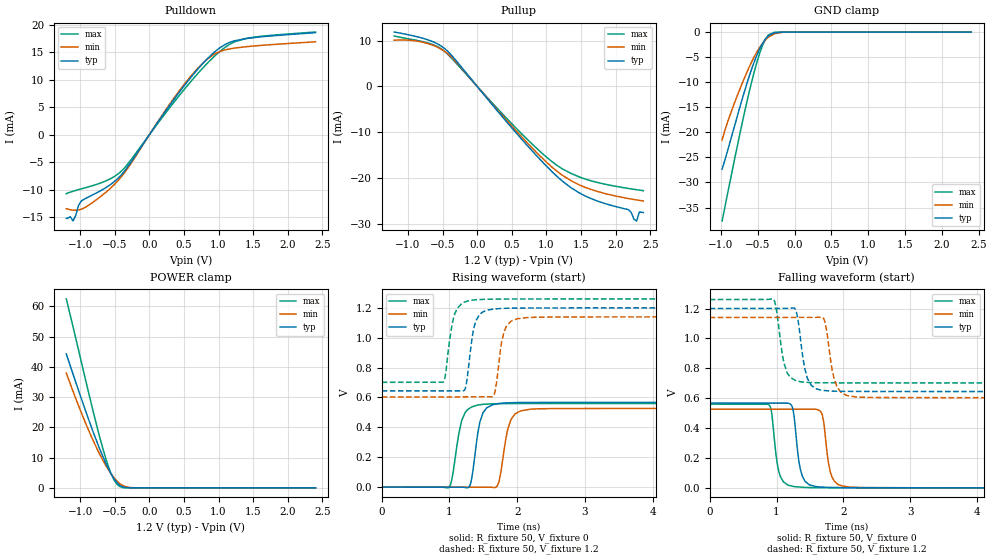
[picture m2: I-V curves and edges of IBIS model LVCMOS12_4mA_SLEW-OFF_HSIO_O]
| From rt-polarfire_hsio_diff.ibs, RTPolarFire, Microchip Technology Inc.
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|   Model LVCMOS12_4mA_SLEW-OFF_HSIO_O
[Model]   LVCMOS12_4mA_SLEW-OFF_HSIO_O
Model_type   Output
Polarity   Non-Inverting
Enable   Active-High
Vmeas =   0.6
Cref =   5p
Rref =   1M
|   typ   min   max
C_comp_pullup   1.335e-12   1.335e-12   1.380e-12
C_comp_pulldown  1.335e-12   1.335e-12   1.380e-12
[Temperature Range]  25C   125C   -55C
[Voltage Range]  1.2   1.14   1.26
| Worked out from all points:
|   slope of the pulldown table from 0 to 0.18 V, typ, clamps not added: 54.1 ohm
|   slope of the pullup table from 0 to 0.18 V, typ, clamps not added: 54.3 ohm
|   GND clamp passes 1 mA (typ) near -0.37 V on its own axis
|   POWER clamp passes 1 mA (typ) near -0.44 V on its own axis
|   rising waveform, R_fixture 50, V_fixture 0: 20-80 % time 115ps typ, 125ps min, 125ps max; typ from 0 V to 0.567 V
|   rising waveform, R_fixture 50, V_fixture 1.2: 20-80 % time 106ps typ, 103ps min, 113ps max; typ from 0.644 V to 1.2 V
|   falling waveform, R_fixture 50, V_fixture 0: 20-80 % time 94.1ps typ, 94.2ps min, 91.7ps max; typ from 0.567 V to 0 V
|   falling waveform, R_fixture 50, V_fixture 1.2: 20-80 % time 116ps typ, 122ps min, 115ps max; typ from 1.2 V to 0.644 V
[GND Clamp]
| Voltage   I(typ)   I(min)   I(max)
-984.4mV  -27.36mA   -21.51mA   -37.68mA
-905.6mV  -23.44mA   -17.74mA   -31.9mA
-826.9mV  -19.32mA   -14.54mA   -26.19mA
-708.7mV  -13.22mA   -10.13mA   -17.93mA
-590.6mV  -7.694mA   -6.183mA   -10.37mA
-511.9mV  -4.598mA   -3.964mA   -6.023mA
-472.5mV  -3.303mA   -3.022mA   -4.164mA
-393.7mV  -1.354mA   -1.536mA   -1.373mA
-354.4mV  -738.1uA   -1.006mA   -579.2uA
-275.6mV  -148.2uA   -350.2uA   -51.36uA
-157.5mV  -6.952uA   -42.62uA   -774.1nA
2.4V      0A         0A         0A
[POWER Clamp]
| Voltage   I(typ)   I(min)   I(max)
-1.2V     44.33mA    38.01mA    62.52mA
-1.063V   34.96mA    29.56mA    49.5mA
-905.6mV  24.47mA    20.57mA    34.21mA
-787.5mV  17.03mA    14.47mA    23.07mA
-669.4mV  10.26mA    9.06mA     12.82mA
-590.6mV  6.299mA    5.966mA    6.995mA
-551.3mV  4.569mA    4.604mA    4.604mA
-472.5mV  1.839mA    2.331mA    1.325mA
-433.1mV  941.2uA    1.473mA    512.6uA
-354.4mV  127.4uA    466.4uA    28.07uA
-196.9mV  963.6nA    26.23uA    495.2nA
2.4V      0A         0A         0A
[Pullup]
| Voltage   I(typ)   I(min)   I(max)
-1.2V     11.9mA     10.11mA    11.03mA
-787.5mV  10.54mA    9.662mA    9.792mA
-590.6mV  9.428mA    8.683mA    8.826mA
-433.1mV  7.788mA    7.254mA    7.146mA
675mV     -12.08mA   -11.54mA   -10.83mA
1.012V    -17.58mA   -16.69mA   -15.58mA
1.239V    -20.78mA   -19.48mA   -18.08mA
1.633V    -24.41mA   -22.43mA   -20.55mA
2.184V    -26.9mA    -24.47mA   -22.27mA
2.303V    -29.38mA   -24.78mA   -22.54mA
2.342V    -27.42mA   -24.87mA   -22.63mA
2.4V      -27.54mA   -25.01mA   -22.75mA
[Pulldown]
| Voltage   I(typ)   I(min)   I(max)
-1.2V     -15.23mA   -13.47mA   -10.74mA
-1.142V   -14.92mA   -13.66mA   -10.45mA
-1.103V   -15.71mA   -13.74mA   -10.29mA
-1.024V   -12.89mA   -13.7mA    -9.995mA
-905.6mV  -11.5mA    -13.07mA   -9.582mA
-590.6mV  -9.322mA   -10.07mA   -8.184mA
-393.7mV  -7.136mA   -7.475mA   -6.504mA
525mV     9.268mA    9.529mA    8.58mA
787.5mV   13.18mA    13.21mA    12.37mA
1.012V    15.78mA    15.13mA    15.11mA
1.397V    17.52mA    16.04mA    17.54mA
2.4V      18.6mA     16.94mA    18.72mA
[Ramp]
dV/dt_r   0.340474/0.114795n  0.316046/0.124803n  0.336016/0.125226n
dV/dt_f   0.333655/0.115787n  0.321999/0.122288n  0.335224/0.114521n
R_load = 50
[Rising Waveform]
R_fixture = 50
V_fixture = 0
V_fixture_min = 0
V_fixture_max = 0
| Time   V(typ)   V(min)   V(max)
0s        1.164uV    2.596uV    1.666uV
986ps     -676.2uV   -507.3uV   -4.508mV
1.034ns   -709.2uV   -532.1uV   49.08mV
1.18ns    -809.5uV   -607.6uV   444.7mV
1.292ns   2.108mV    -665.5uV   526.3mV
1.49ns    491.4mV    -767.9uV   553.8mV
1.705ns   557.2mV    7.534mV    558.2mV
1.91ns    564.7mV    455.6mV    559.2mV
2.2ns     566.3mV    521.8mV    559.4mV
10ns      567.5mV    526.7mV    560mV
[Rising Waveform]
R_fixture = 50
V_fixture = 1.2
V_fixture_min = 1.14
V_fixture_max = 1.26
| Time   V(typ)   V(min)   V(max)
0s        643.9mV    603.3mV    701.3mV
909ps     644.2mV    603.8mV    704mV
1.058ns   644.3mV    603.9mV    1.129V
1.229ns   655.4mV    604mV      1.24V
1.324ns   965.5mV    604.1mV    1.251V
1.444ns   1.157V     604.1mV    1.255V
1.641ns   1.191V     606.6mV    1.258V
1.803ns   1.197V     1.037V     1.259V
2.107ns   1.199V     1.133V     1.259V
10ns      1.2V       1.14V      1.26V
[Falling Waveform]
R_fixture = 50
V_fixture = 0
V_fixture_min = 0
V_fixture_max = 0
| Time   V(typ)   V(min)   V(max)
0s        567.5mV    526.7mV    560mV
891ps     566.9mV    526.4mV    553.2mV
1.035ns   566.8mV    526.3mV    107.5mV
1.264ns   473.6mV    526.2mV    8.17mV
1.336ns   174.3mV    526.2mV    5.848mV
1.425ns   44.6mV     526.2mV    2.977mV
1.672ns   4.932mV    501.9mV    1.278mV
1.805ns   2.342mV    106mV      1.023mV
1.986ns   1.41mV     11.99mV    707.7uV
10ns      1.935uV    4.516uV    2.517uV
[Falling Waveform]
R_fixture = 50
V_fixture = 1.2
V_fixture_min = 1.14
V_fixture_max = 1.26
| Time   V(typ)   V(min)   V(max)
0s        1.2V       1.14V      1.26V
960ps     1.201V     1.141V     1.26V
1.159ns   1.201V     1.141V     769.3mV
1.293ns   1.184V     1.141V     716.1mV
1.39ns    886.7mV    1.141V     707.9mV
1.519ns   686.1mV    1.141V     704.4mV
1.701ns   652.1mV    1.135V     703.1mV
1.903ns   646.5mV    677.4mV    702.6mV
2.191ns   645.3mV    607.8mV    702.1mV
10ns      643.9mV    603.3mV    701.3mV
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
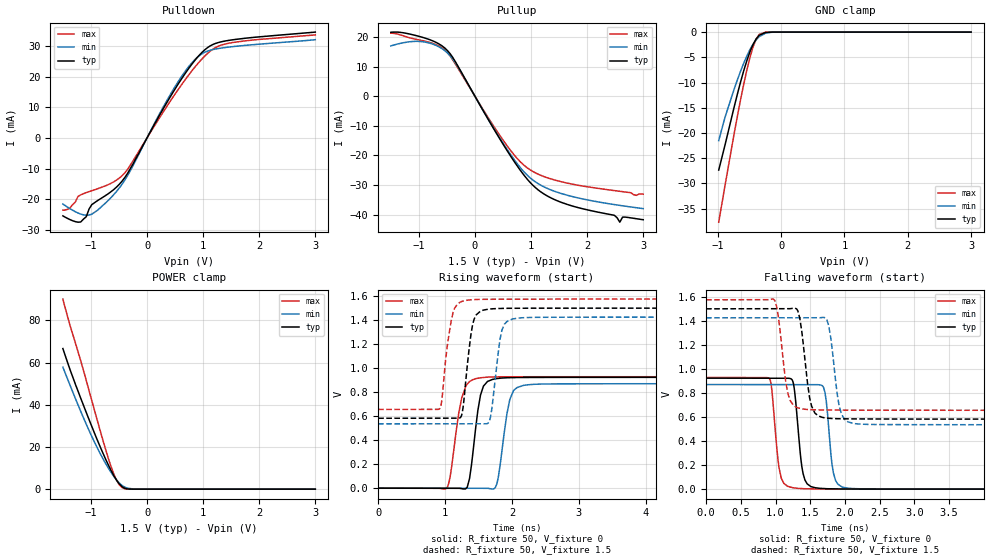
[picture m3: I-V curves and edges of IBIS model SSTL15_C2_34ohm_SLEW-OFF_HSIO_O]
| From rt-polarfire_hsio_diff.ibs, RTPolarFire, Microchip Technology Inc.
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|   Model SSTL15_C2_34ohm_SLEW-OFF_HSIO_O
[Model]   SSTL15_C2_34ohm_SLEW-OFF_HSIO_O
Model_type   Output
Polarity   Non-Inverting
Enable   Active-High
Vmeas =   0.75
Cref =   5p
Rref =   50
Vref =   0.75
|   typ   min   max
C_comp_pullup   1.335e-12   1.335e-12   1.380e-12
C_comp_pulldown  1.335e-12   1.335e-12   1.380e-12
[Temperature Range]  25C   125C   -55C
[Voltage Range]  1.5   1.425   1.575
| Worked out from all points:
|   slope of the pulldown table from 0 to 0.225 V, typ, clamps not added: 30.1 ohm
|   slope of the pullup table from 0 to 0.225 V, typ, clamps not added: 30.2 ohm
|   GND clamp passes 1 mA (typ) near -0.37 V on its own axis
|   POWER clamp passes 1 mA (typ) near -0.43 V on its own axis
|   rising waveform, R_fixture 50, V_fixture 0: 20-80 % time 126ps typ, 134ps min, 146ps max; typ from 0 V to 0.923 V
|   rising waveform, R_fixture 50, V_fixture 1.5: 20-80 % time 110ps typ, 114ps min, 120ps max; typ from 0.582 V to 1.5 V
|   falling waveform, R_fixture 50, V_fixture 0: 20-80 % time 91.1ps typ, 85.8ps min, 88.4ps max; typ from 0.923 V to 0 V
|   falling waveform, R_fixture 50, V_fixture 1.5: 20-80 % time 112ps typ, 111ps min, 114ps max; typ from 1.5 V to 0.582 V
[GND Clamp]
| Voltage   I(typ)   I(min)   I(max)
-984.4mV  -27.37mA   -21.52mA   -37.7mA
-885.9mV  -22.43mA   -16.92mA   -30.48mA
-738.3mV  -14.72mA   -11.21mA   -19.96mA
-639.8mV  -9.903mA   -7.76mA    -13.42mA
-590.6mV  -7.7mA     -6.188mA   -10.38mA
-492.2mV  -3.93mA    -3.481mA   -5.066mA
-443mV    -2.467mA   -2.402mA   -2.955mA
-393.7mV  -1.355mA   -1.538mA   -1.375mA
-344.5mV  -621.9uA   -897uA     -448.3uA
-246.1mV  -72.57uA   -218.4uA   -18.4uA
-49.22mV  -334.5nA   -3.793uA   -95.68nA
3V        0A         0A         0A
[POWER Clamp]
| Voltage   I(typ)   I(min)   I(max)
-1.5V     66.64mA    57.8mA     90.1mA
-1.378V   57.06mA    49.6mA     78.07mA
-1.28V    49.9mA     43.13mA    69.49mA
-1.034V   32.99mA    27.83mA    46.7mA
-836.7mV  20.16mA    16.97mA    27.85mA
-689.1mV  11.42mA    9.956mA    14.55mA
-590.6mV  6.331mA    6.012mA    7.055mA
-541.4mV  4.184mA    4.318mA    4.125mA
-443mV    1.134mA    1.688mA    703.5uA
-344.5mV  93.53uA    432.5uA    21.45uA
-49.22mV  620.3nA    2.506uA    250nA
3V        0A         0A         0A
[Pullup]
| Voltage   I(typ)   I(min)   I(max)
-1.5V     21.63mA    17.01mA    21.33mA
-935.2mV  19.92mA    18.44mA    18.8mA
-492.2mV  15.48mA    14.7mA     14.8mA
-344.5mV  11.55mA    11.2mA     10.76mA
609.4mV   -19.45mA   -18.96mA   -17.67mA
890.6mV   -27.08mA   -25.9mA    -23.58mA
1.172V    -32.3mA    -30.05mA   -26.72mA
1.648V    -36.59mA   -33.48mA   -29.37mA
2.484V    -40.25mA   -36.62mA   -31.9mA
2.583V    -42.58mA   -36.9mA    -32.14mA
2.632V    -40.87mA   -37.04mA   -32.26mA
3V        -41.75mA   -38mA      -33.11mA
[Pulldown]
| Voltage   I(typ)   I(min)   I(max)
-1.5V     -25.45mA   -21.56mA   -23.56mA
-1.378V   -26.63mA   -23.05mA   -22.94mA
-1.181V   -27.44mA   -24.88mA   -18.59mA
-1.083V   -25.71mA   -25.25mA   -17.85mA
-984.4mV  -21.76mA   -24.89mA   -17.24mA
-639.8mV  -17.54mA   -19.44mA   -14.8mA
-344.5mV  -11.51mA   -12.23mA   -10.2mA
609.4mV   19.12mA    19.87mA    17.2mA
843.8mV   25.11mA    25.39mA    22.9mA
1.078V    29.46mA    28.34mA    27.57mA
1.5V      31.96mA    29.74mA    31.05mA
3V        34.55mA    32.06mA    33.63mA
[Ramp]
dV/dt_r   0.554086/0.1257n  0.522123/0.134094n  0.557308/0.145919n
dV/dt_f   0.550552/0.11238n  0.533607/0.111144n  0.551505/0.113848n
R_load = 50
[Rising Waveform]
R_fixture = 50
V_fixture = 0
V_fixture_min = 0
V_fixture_max = 0
| Time   V(typ)   V(min)   V(max)
0s        1.606uV    2.686uV    2.4uV
1.032ns   -812.8uV   -590.7uV   5.258mV
1.205ns   -949.3uV   -690.2uV   625.2mV
1.305ns   -6.307mV   -747.7uV   840.1mV
1.366ns   79.83mV    -782.8uV   888.1mV
1.52ns    743mV      -871.4uV   919mV
1.774ns   912.6mV    34.68mV    926.7mV
1.967ns   920.1mV    735.7mV    927.4mV
2.172ns   921.9mV    856.1mV    928mV
10ns      923.5mV    870.2mV    928.8mV
[Rising Waveform]
R_fixture = 50
V_fixture = 1.5
V_fixture_min = 1.425
V_fixture_max = 1.575
| Time   V(typ)   V(min)   V(max)
0s        582.4mV    535.6mV    655.8mV
920ps     582.9mV    536.1mV    663.2mV
1.12ns    583mV      536.2mV    1.464V
1.243ns   600.9mV    536.3mV    1.554V
1.294ns   801.6mV    536.3mV    1.562V
1.469ns   1.445V     536.4mV    1.571V
1.667ns   1.492V     566mV      1.573V
1.85ns    1.497V     1.316V     1.574V
2.011ns   1.498V     1.41V      1.574V
10ns      1.5V       1.425V     1.575V
[Falling Waveform]
R_fixture = 50
V_fixture = 0
V_fixture_min = 0
V_fixture_max = 0
| Time   V(typ)   V(min)   V(max)
0s        923.5mV    870.2mV    928.8mV
913ps     922.7mV    869.7mV    918.5mV
1.05ns    922.6mV    869.7mV    178.1mV
1.249ns   895.5mV    869.5mV    11.64mV
1.396ns   130.5mV    869.5mV    4.359mV
1.573ns   11.71mV    869.4mV    2.076mV
1.711ns   4.662mV    806.2mV    1.583mV
1.864ns   2.304mV    72.37mV    1.1mV
2.037ns   1.526mV    8.775mV    968.8uV
10ns      2.565uV    4.027uV    3.113uV
[Falling Waveform]
R_fixture = 50
V_fixture = 1.5
V_fixture_min = 1.425
V_fixture_max = 1.575
| Time   V(typ)   V(min)   V(max)
0s        1.5V       1.425V     1.575V
989ps     1.501V     1.425V     1.569V
1.172ns   1.501V     1.426V     808.7mV
1.322ns   1.481V     1.426V     676.6mV
1.399ns   1.208V     1.426V     666.3mV
1.566ns   633.2mV    1.426V     659.8mV
1.738ns   591.4mV    1.409V     658.4mV
1.914ns   585.7mV    697.3mV    657.7mV
2.128ns   584.5mV    545.6mV    657mV
10ns      582.4mV    535.6mV    655.8mV
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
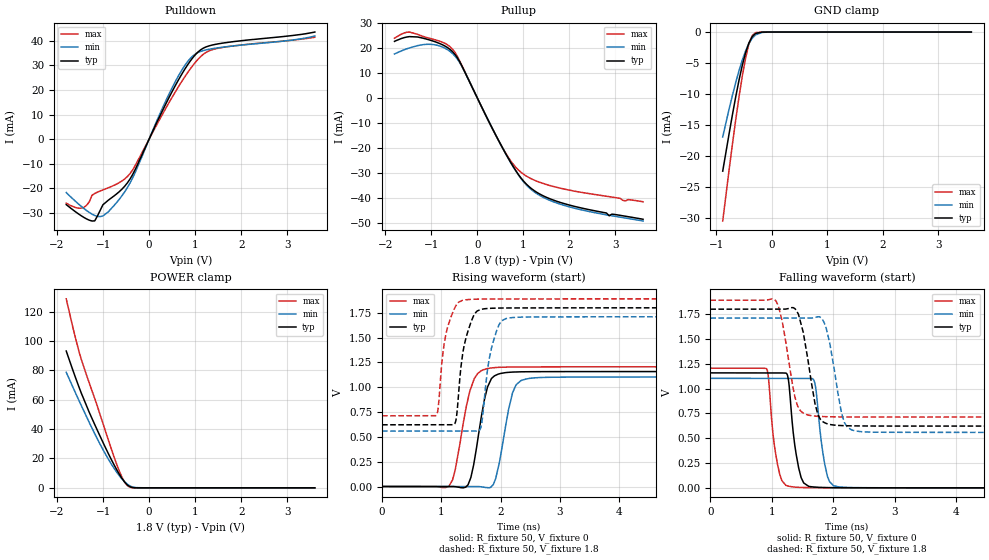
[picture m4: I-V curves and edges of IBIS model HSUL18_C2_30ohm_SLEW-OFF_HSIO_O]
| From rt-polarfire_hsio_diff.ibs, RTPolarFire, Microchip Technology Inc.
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|   Model HSUL18_C2_30ohm_SLEW-OFF_HSIO_O
[Model]   HSUL18_C2_30ohm_SLEW-OFF_HSIO_O
Model_type   Output
Polarity   Non-Inverting
Enable   Active-High
Vmeas =   0.9
Cref =   5p
Rref =   50
Vref =   0.9
|   typ   min   max
C_comp_pullup   1.335e-12   1.335e-12   1.380e-12
C_comp_pulldown  1.335e-12   1.335e-12   1.380e-12
[Temperature Range]  25C   125C   -55C
[Voltage Range]  1.8   1.71   1.89
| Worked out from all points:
|   slope of the pulldown table from 0 to 0.27 V, typ, clamps not added: 25 ohm
|   slope of the pullup table from 0 to 0.27 V, typ, clamps not added: 26.6 ohm
|   GND clamp passes 1 mA (typ) near -0.37 V on its own axis
|   POWER clamp passes 1 mA (typ) near -0.43 V on its own axis
|   rising waveform, R_fixture 50, V_fixture 0: 20-80 % time 199ps typ, 205ps min, 226ps max; typ from 0 V to 1.16 V
|   rising waveform, R_fixture 50, V_fixture 1.8: 20-80 % time 168ps typ, 175ps min, 162ps max; typ from 0.622 V to 1.8 V
|   falling waveform, R_fixture 50, V_fixture 0: 20-80 % time 131ps typ, 130ps min, 127ps max; typ from 1.16 V to 0 V
|   falling waveform, R_fixture 50, V_fixture 1.8: 20-80 % time 188ps typ, 189ps min, 189ps max; typ from 1.8 V to 0.622 V
[GND Clamp]
| Voltage   I(typ)   I(min)   I(max)
-885.9mV  -22.44mA   -16.92mA   -30.49mA
-708.7mV  -13.24mA   -10.14mA   -17.96mA
-649.7mV  -10.37mA   -8.095mA   -14.06mA
-590.6mV  -7.705mA   -6.193mA   -10.39mA
-531.6mV  -5.322mA   -4.488mA   -7.054mA
-472.5mV  -3.308mA   -3.028mA   -4.171mA
-413.4mV  -1.757mA   -1.859mA   -1.935mA
-354.4mV  -739.5uA   -1.008mA   -580.7uA
-295.3mV  -232.3uA   -469.6uA   -100.4uA
-177.2mV  -12.01uA   -62.89uA   -1.688uA
-59.06mV  -489.8nA   -5.037uA   -176.4nA
3.6V      0A         0A         0A
[POWER Clamp]
| Voltage   I(typ)   I(min)   I(max)
-1.8V     93.11mA    78.62mA    128.6mA
-1.595V   74.64mA    64.3mA     101.3mA
-1.477V   64.73mA    56.26mA    87.68mA
-1.299V   51.32mA    44.43mA    71.22mA
-1.063V   35.01mA    29.59mA    49.65mA
-885.9mV  23.32mA    19.56mA    32.61mA
-708.7mV  12.62mA    10.87mA    16.4mA
-590.6mV  6.476mA    6.104mA    7.295mA
-472.5mV  1.932mA    2.452mA    1.539mA
-354.4mV  154uA      480.4uA    74.19uA
-59.06mV  800.7nA    2.877uA    466.9nA
3.6V      0A         0A         0A
[Pullup]
| Voltage   I(typ)   I(min)   I(max)
-1.8V     22.73mA    17.67mA    24.01mA
-1.477V   24.64mA    20.09mA    26.49mA
-1.063V   23.43mA    21.57mA    24.08mA
-531.6mV  18.47mA    17.72mA    19.44mA
-354.4mV  13.52mA    13.3mA     13.83mA
562.5mV   -20.53mA   -20.57mA   -20.44mA
787.5mV   -27.75mA   -27.87mA   -26.77mA
1.012V    -33.52mA   -33.81mA   -30.69mA
1.35V     -38.47mA   -39.03mA   -33.78mA
1.8V      -41.88mA   -42.58mA   -36.16mA
2.863V    -47.25mA   -47.06mA   -39.57mA
3.6V      -48.65mA   -49.35mA   -41.62mA
[Pulldown]
| Voltage   I(typ)   I(min)   I(max)
-1.8V     -26.65mA   -21.75mA   -26.06mA
-1.417V   -31.86mA   -28.23mA   -27.77mA
-1.181V   -33.27mA   -31.08mA   -22.13mA
-1.004V   -26.72mA   -31.27mA   -20.66mA
-885.9mV  -24.85mA   -29.57mA   -19.8mA
-590.6mV  -20.37mA   -23.06mA   -17.03mA
-413.4mV  -16.19mA   -17.81mA   -14mA
562.5mV   21.56mA    23.18mA    19.01mA
843.8mV   30.43mA    31.72mA    27.25mA
1.125V    36.41mA    35.74mA    33.68mA
1.575V    39mA       37.35mA    37.24mA
3.6V      43.57mA    41.94mA    41.46mA
[Ramp]
dV/dt_r   0.694964/0.198754n  0.661911/0.205125n  0.723435/0.226379n
dV/dt_f   0.707015/0.188312n  0.690938/0.189433n  0.70655/0.189308n
R_load = 50
[Rising Waveform]
R_fixture = 50
V_fixture = 0
V_fixture_min = 0
V_fixture_max = 0
| Time   V(typ)   V(min)   V(max)
0s        2.204uV    3.315uV    3.494uV
1.127ns   -363.4uV   -479.3uV   2.197mV
1.231ns   -1.877mV   -523.9uV   161.9mV
1.41ns    -6.599mV   -600.5uV   772.7mV
1.555ns   256.1mV    -662.6uV   1.087V
1.774ns   992.2mV    -11.38mV   1.188V
1.915ns   1.12V      78.68mV    1.198V
2.199ns   1.153V     941.7mV    1.203V
2.428ns   1.156V     1.083V     1.204V
10ns      1.158V     1.103V     1.206V
[Rising Waveform]
R_fixture = 50
V_fixture = 1.8
V_fixture_min = 1.71
V_fixture_max = 1.89
| Time   V(typ)   V(min)   V(max)
0s        621.6mV    558.4mV    712.4mV
917ps     622mV      558.7mV    719.6mV
1.068ns   622.1mV    558.8mV    1.509V
1.233ns   641.6mV    558.8mV    1.808V
1.355ns   1.318V     558.9mV    1.875V
1.503ns   1.663V     558.9mV    1.885V
1.659ns   1.783V     583.4mV    1.888V
1.846ns   1.795V     1.398V     1.889V
2.092ns   1.798V     1.692V     1.889V
10ns      1.8V       1.71V      1.89V
[Falling Waveform]
R_fixture = 50
V_fixture = 0
V_fixture_min = 0
V_fixture_max = 0
| Time   V(typ)   V(min)   V(max)
0s        1.158V     1.103V     1.206V
920ps     1.158V     1.103V     1.196V
1.097ns   1.157V     1.103V     229.4mV
1.295ns   950.5mV    1.102V     13.79mV
1.398ns   338.1mV    1.102V     6.478mV
1.521ns   49.06mV    1.102V     3.263mV
1.702ns   7.819mV    1.057V     1.89mV
1.908ns   2.574mV    113.5mV    1.295mV
2.095ns   1.625mV    9.152mV    991uV
10ns      3.134uV    3.824uV    4.013uV
[Falling Waveform]
R_fixture = 50
V_fixture = 1.8
V_fixture_min = 1.71
V_fixture_max = 1.89
| Time   V(typ)   V(min)   V(max)
0s        1.8V       1.71V      1.89V
1.071ns   1.801V     1.71V      1.881V
1.17ns    1.801V     1.711V     1.682V
1.396ns   1.793V     1.711V     877.2mV
1.61ns    1.207V     1.711V     731.2mV
1.794ns   689.2mV    1.717V     719.1mV
1.947ns   638.7mV    1.451V     716mV
2.18ns    626.3mV    661.1mV    714.1mV
2.372ns   624.1mV    572.4mV    713.5mV
10ns      621.6mV    558.4mV    712.4mV
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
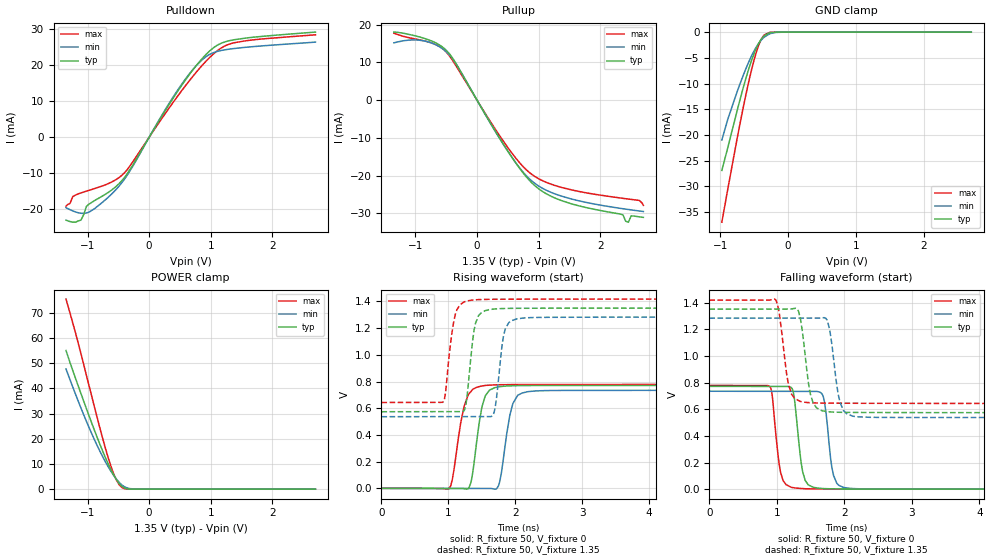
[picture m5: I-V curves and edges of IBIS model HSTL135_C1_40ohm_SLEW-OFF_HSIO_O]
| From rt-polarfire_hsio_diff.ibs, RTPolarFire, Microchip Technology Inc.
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|   Model HSTL135_C1_40ohm_SLEW-OFF_HSIO_O
[Model]   HSTL135_C1_40ohm_SLEW-OFF_HSIO_O
Model_type   Output
Polarity   Non-Inverting
Enable   Active-High
Vmeas =   0.675
Cref =   5p
Rref =   50
Vref =   0.675
|   typ   min   max
C_comp_pullup   1.335e-12   1.335e-12   1.380e-12
C_comp_pulldown  1.335e-12   1.335e-12   1.380e-12
[Temperature Range]  25C   125C   -55C
[Voltage Range]  1.35   1.2825   1.4175
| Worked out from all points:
|   slope of the pulldown table from 0 to 0.203 V, typ, clamps not added: 35.1 ohm
|   slope of the pullup table from 0 to 0.203 V, typ, clamps not added: 35.8 ohm
|   GND clamp passes 1 mA (typ) near -0.37 V on its own axis
|   POWER clamp passes 1 mA (typ) near -0.43 V on its own axis
|   rising waveform, R_fixture 50, V_fixture 0: 20-80 % time 131ps typ, 138ps min, 152ps max; typ from 0 V to 0.771 V
|   rising waveform, R_fixture 50, V_fixture 1.35: 20-80 % time 101ps typ, 100ps min, 113ps max; typ from 0.574 V to 1.35 V
|   falling waveform, R_fixture 50, V_fixture 0: 20-80 % time 101ps typ, 97.4ps min, 97.6ps max; typ from 0.771 V to 0 V
|   falling waveform, R_fixture 50, V_fixture 1.35: 20-80 % time 116ps typ, 119ps min, 117ps max; typ from 1.35 V to 0.574 V
[GND Clamp]
| Voltage   I(typ)   I(min)   I(max)
-974.5mV  -26.9mA    -20.99mA   -36.97mA
-885.9mV  -22.43mA   -16.91mA   -30.47mA
-753mV    -15.48mA   -11.75mA   -20.97mA
-664.5mV  -11.06mA   -8.585mA   -15mA
-575.9mV  -7.072mA   -5.739mA   -9.511mA
-487.3mV  -3.767mA   -3.362mA   -4.833mA
-443mV    -2.466mA   -2.401mA   -2.954mA
-398.7mV  -1.449mA   -1.613mA   -1.504mA
-354.4mV  -738.4uA   -1.007mA   -579.6uA
-265.8mV  -117.5uA   -300.6uA   -36.61uA
-44.3mV   -274.4nA   -3.251uA   -69.5nA
2.7V      0A         0A         0A
[POWER Clamp]
| Voltage   I(typ)   I(min)   I(max)
-1.35V    55.07mA    47.72mA    75.49mA
-1.196V   44.05mA    37.75mA    62.13mA
-974.5mV  29.03mA    24.41mA    40.95mA
-797.3mV  17.68mA    14.97mA    24.06mA
-664.5mV  10.01mA    8.871mA    12.44mA
-575.9mV  5.63mA     5.451mA    6.064mA
-531.6mV  3.786mA    3.983mA    3.599mA
-487.3mV  2.262mA    2.712mA    1.789mA
-443mV    1.133mA    1.675mA    684.4uA
-354.4mV  127.5uA    473.3uA    30.46uA
-221.5mV  1.715uA    56.89uA    636.6nA
2.7V      0A         0A         0A
[Pullup]
| Voltage   I(typ)   I(min)   I(max)
-1.35V    18.04mA    15.2mA     17.73mA
-885.9mV  16.53mA    15.79mA    15.82mA
-487.3mV  13.01mA    12.65mA    12.53mA
-310.1mV  8.812mA    8.824mA    8.267mA
548.4mV   -14.7mA    -14.71mA   -13.63mA
801.6mV   -20.34mA   -20.04mA   -18.46mA
1.012V    -23.61mA   -22.86mA   -20.91mA
1.527V    -27.42mA   -26.14mA   -23.72mA
2.369V    -30.37mA   -28.74mA   -25.99mA
2.457V    -32.31mA   -28.95mA   -26.18mA
2.502V    -30.63mA   -29.05mA   -26.27mA
2.7V      -31.04mA   -29.49mA   -27.85mA
[Pulldown]
| Voltage   I(typ)   I(min)   I(max)
-1.35V    -23.02mA   -19.55mA   -19.16mA
-1.285V   -23.4mA    -20.12mA   -18.36mA
-1.24V    -23.57mA   -20.45mA   -16.47mA
-1.107V   -23mA      -21.11mA   -15.45mA
-1.019V   -19.21mA   -21.03mA   -14.96mA
-575.9mV  -14.21mA   -15.21mA   -12.13mA
-354.4mV  -10.11mA   -10.49mA   -8.961mA
548.4mV   14.91mA    15.2mA     13.39mA
843.8mV   21.52mA    21.25mA    19.64mA
1.055V    24.98mA    23.57mA    23.3mA
1.394V    27.13mA    24.68mA    26.29mA
2.7V      29.21mA    26.42mA    28.45mA
[Ramp]
dV/dt_r   0.462738/0.131441n  0.440662/0.137687n  0.466821/0.152072n
dV/dt_f   0.465721/0.116446n  0.447459/0.119079n  0.464673/0.116802n
R_load = 50
[Rising Waveform]
R_fixture = 50
V_fixture = 0
V_fixture_min = 0
V_fixture_max = 0
| Time   V(typ)   V(min)   V(max)
0s        1.383uV    2.546uV    2.011uV
1.004ns   -451.9uV   -467.8uV   -5.037mV
1.236ns   -2.933mV   -576.5uV   616.3mV
1.304ns   -246.9uV   -608.3uV   705.9mV
1.491ns   579.5mV    -695.9uV   766.1mV
1.552ns   693.6mV    -724.5uV   770.3mV
1.75ns    760.1mV    20.79mV    775.9mV
1.964ns   768.2mV    635.3mV    776.9mV
2.186ns   769.9mV    723.8mV    777.1mV
10ns      771.2mV    734.4mV    778mV
[Rising Waveform]
R_fixture = 50
V_fixture = 1.35
V_fixture_min = 1.2825
V_fixture_max = 1.4175
| Time   V(typ)   V(min)   V(max)
0s        573.8mV    536.7mV    643mV
926ps     574.5mV    537.1mV    650.5mV
1.102ns   574.7mV    537.1mV    1.299V
1.243ns   589.1mV    537.2mV    1.397V
1.352ns   1.056V     537.2mV    1.41V
1.45ns    1.292V     537.3mV    1.414V
1.67ns    1.342V     552.2mV    1.416V
1.825ns   1.347V     1.145V     1.416V
2.02ns    1.348V     1.269V     1.416V
10ns      1.35V      1.282V     1.417V
[Falling Waveform]
R_fixture = 50
V_fixture = 0
V_fixture_min = 0
V_fixture_max = 0
| Time   V(typ)   V(min)   V(max)
0s        771.2mV    734.5mV    778mV
898ps     770.5mV    733.9mV    768.2mV
1.054ns   770.4mV    733.8mV    129.4mV
1.228ns   751.9mV    733.7mV    12.75mV
1.283ns   572.8mV    733.7mV    8.13mV
1.42ns    65.59mV    733.6mV    3.183mV
1.681ns   5.017mV    702.7mV    1.451mV
1.84ns    2.165mV    103.2mV    1.201mV
1.988ns   1.544mV    13.16mV    969uV
10ns      2.06uV     4.055uV    2.865uV
[Falling Waveform]
R_fixture = 50
V_fixture = 1.35
V_fixture_min = 1.2825
V_fixture_max = 1.4175
| Time   V(typ)   V(min)   V(max)
0s        1.35V      1.282V     1.417V
985ps     1.351V     1.283V     1.419V
1.17ns    1.351V     1.283V     789.9mV
1.322ns   1.333V     1.283V     664.8mV
1.402ns   1.084V     1.283V     652.6mV
1.589ns   609.6mV    1.283V     646.4mV
1.746ns   581.6mV    1.267V     645.2mV
1.936ns   576.6mV    651.9mV    644.8mV
2.127ns   575.7mV    547.1mV    644.4mV
10ns      573.8mV    536.7mV    643mV
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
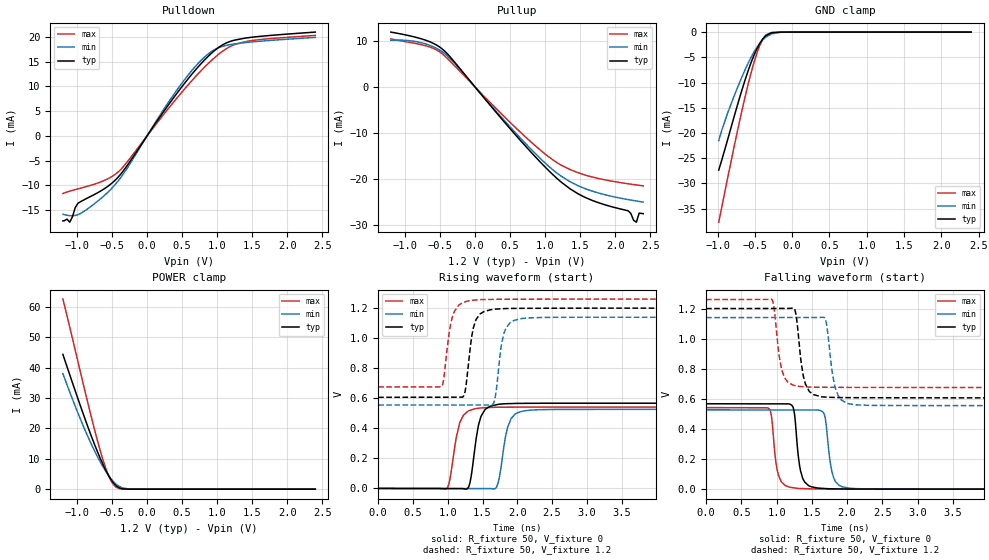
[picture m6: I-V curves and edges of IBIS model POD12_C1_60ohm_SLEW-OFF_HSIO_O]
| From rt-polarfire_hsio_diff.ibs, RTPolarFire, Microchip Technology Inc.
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|   Model POD12_C1_60ohm_SLEW-OFF_HSIO_O
[Model]   POD12_C1_60ohm_SLEW-OFF_HSIO_O
Model_type   Output
Polarity   Non-Inverting
Enable   Active-High
Vmeas =   0.84
Cref =   5p
Rref =   50
Vref =   0.84
|   typ   min   max
C_comp_pullup   1.335e-12   1.335e-12   1.380e-12
C_comp_pulldown  1.335e-12   1.335e-12   1.380e-12
[Temperature Range]  25C   125C   -55C
[Voltage Range]  1.2   1.14   1.26
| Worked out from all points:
|   slope of the pulldown table from 0 to 0.18 V, typ, clamps not added: 48.1 ohm
|   slope of the pullup table from 0 to 0.18 V, typ, clamps not added: 54.3 ohm
|   GND clamp passes 1 mA (typ) near -0.37 V on its own axis
|   POWER clamp passes 1 mA (typ) near -0.44 V on its own axis
|   rising waveform, R_fixture 50, V_fixture 0: 20-80 % time 115ps typ, 120ps min, 123ps max; typ from 0 V to 0.567 V
|   rising waveform, R_fixture 50, V_fixture 1.2: 20-80 % time 103ps typ, 101ps min, 109ps max; typ from 0.606 V to 1.2 V
|   falling waveform, R_fixture 50, V_fixture 0: 20-80 % time 80ps typ, 86.5ps min, 78.8ps max; typ from 0.567 V to 0 V
|   falling waveform, R_fixture 50, V_fixture 1.2: 20-80 % time 97.5ps typ, 104ps min, 94.6ps max; typ from 1.2 V to 0.606 V
[GND Clamp]
| Voltage   I(typ)   I(min)   I(max)
-984.4mV  -27.36mA   -21.51mA   -37.68mA
-866.2mV  -21.39mA   -16.1mA    -29.03mA
-787.5mV  -17.26mA   -13.03mA   -23.38mA
-669.4mV  -11.29mA   -8.751mA   -15.31mA
-590.6mV  -7.694mA   -6.183mA   -10.37mA
-511.9mV  -4.598mA   -3.964mA   -6.023mA
-472.5mV  -3.303mA   -3.022mA   -4.164mA
-393.7mV  -1.354mA   -1.536mA   -1.373mA
-354.4mV  -738.1uA   -1.006mA   -579.2uA
-275.6mV  -148.2uA   -350.2uA   -51.36uA
-157.5mV  -6.952uA   -42.62uA   -774.1nA
2.4V      0A         0A         0A
[POWER Clamp]
| Voltage   I(typ)   I(min)   I(max)
-1.2V     44.33mA    38.01mA    62.52mA
-1.063V   34.96mA    29.56mA    49.5mA
-905.6mV  24.47mA    20.57mA    34.21mA
-787.5mV  17.03mA    14.47mA    23.07mA
-669.4mV  10.26mA    9.06mA     12.82mA
-590.6mV  6.299mA    5.966mA    6.995mA
-551.3mV  4.569mA    4.604mA    4.604mA
-472.5mV  1.839mA    2.331mA    1.325mA
-433.1mV  941.2uA    1.473mA    512.6uA
-354.4mV  127.4uA    466.4uA    28.07uA
-196.9mV  963.6nA    26.23uA    495.2nA
2.4V      0A         0A         0A
[Pullup]
| Voltage   I(typ)   I(min)   I(max)
-1.2V     11.9mA     10.11mA    10.42mA
-787.5mV  10.54mA    9.662mA    9.248mA
-590.6mV  9.428mA    8.683mA    8.336mA
-433.1mV  7.788mA    7.254mA    6.749mA
787.5mV   -13.97mA   -13.33mA   -11.8mA
1.125V    -19.25mA   -18.19mA   -15.99mA
1.357V    -22.14mA   -20.6mA    -17.95mA
1.712V    -24.88mA   -22.81mA   -19.71mA
2.184V    -26.9mA    -24.47mA   -21.04mA
2.303V    -29.38mA   -24.78mA   -21.3mA
2.342V    -27.42mA   -24.87mA   -21.38mA
2.4V      -27.54mA   -25.01mA   -21.49mA
[Pulldown]
| Voltage   I(typ)   I(min)   I(max)
-1.2V     -17.14mA   -15.78mA   -11.63mA
-1.142V   -16.78mA   -16.01mA   -11.32mA
-1.103V   -17.4mA    -16.09mA   -11.14mA
-1.024V   -14.44mA   -16.04mA   -10.83mA
-945mV    -13.24mA   -15.63mA   -10.53mA
-590.6mV  -10.49mA   -11.79mA   -8.865mA
-393.7mV  -8.027mA   -8.748mA   -7.045mA
450mV     9.043mA    9.725mA    8.039mA
900mV     16.43mA    16.83mA    14.96mA
1.125V    18.71mA    18.24mA    17.54mA
1.397V    19.72mA    18.82mA    19mA
2.4V      20.94mA    19.87mA    20.27mA
[Ramp]
dV/dt_r   0.340476/0.114691n  0.316048/0.119515n  0.32506/0.122562n
dV/dt_f   0.356127/97.4762p  0.351105/0.103508n  0.350904/94.5778p
R_load = 50
[Rising Waveform]
R_fixture = 50
V_fixture = 0
V_fixture_min = 0
V_fixture_max = 0
| Time   V(typ)   V(min)   V(max)
0s        1.174uV    2.488uV    1.669uV
980ps     -681.8uV   -514.2uV   -4.065mV
1.173ns   -816.3uV   -615.9uV   438.2mV
1.277ns   -3.629mV   -670.8uV   508.2mV
1.319ns   36.27mV    -692.9uV   519.2mV
1.478ns   479.8mV    -776.8uV   535.6mV
1.735ns   560.6mV    57.83mV    540.5mV
1.86ns    564mV      405.7mV    540.7mV
2.106ns   566.2mV    516.7mV    541mV
10ns      567.5mV    526.7mV    541.8mV
[Rising Waveform]
R_fixture = 50
V_fixture = 1.2
V_fixture_min = 1.14
V_fixture_max = 1.26
| Time   V(typ)   V(min)   V(max)
0s        606.4mV    554.8mV    675.2mV
911ps     607mV      555.1mV    678.2mV
1.064ns   607.1mV    555.1mV    1.138V
1.233ns   618.3mV    555.1mV    1.239V
1.338ns   987.7mV    555.2mV    1.251V
1.464ns   1.161V     555.2mV    1.256V
1.658ns   1.191V     566.3mV    1.258V
1.81ns    1.196V     1.035V     1.259V
2.067ns   1.198V     1.131V     1.259V
10ns      1.2V       1.14V      1.26V
[Falling Waveform]
R_fixture = 50
V_fixture = 0
V_fixture_min = 0
V_fixture_max = 0
| Time   V(typ)   V(min)   V(max)
0s        567.5mV    526.7mV    541.8mV
891ps     566.9mV    526.4mV    535mV
1.027ns   566.8mV    526.3mV    91.44mV
1.211ns   558.8mV    526.3mV    11.09mV
1.37ns    71.99mV    526.2mV    4.004mV
1.583ns   7.414mV    525.7mV    1.328mV
1.684ns   4.383mV    485.4mV    1.115mV
1.811ns   2.028mV    73.5mV     874.6uV
2.021ns   1.175mV    6.864mV    639.9uV
10ns      2.416uV    3.893uV    2.466uV
[Falling Waveform]
R_fixture = 50
V_fixture = 1.2
V_fixture_min = 1.14
V_fixture_max = 1.26
| Time   V(typ)   V(min)   V(max)
0s        1.2V       1.14V      1.26V
932ps     1.201V     1.14V      1.261V
1.07ns    1.201V     1.14V      796.7mV
1.255ns   1.196V     1.141V     688.8mV
1.323ns   952.9mV    1.141V     682.6mV
1.409ns   698.3mV    1.141V     679.6mV
1.682ns   612.2mV    1.138V     677mV
1.829ns   609.2mV    677mV      676.6mV
2.106ns   607.8mV    561mV      676.2mV
10ns      606.4mV    554.8mV    675.1mV
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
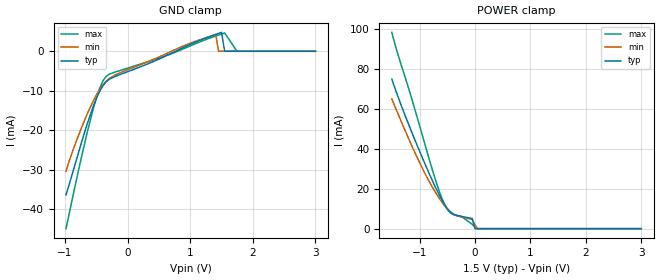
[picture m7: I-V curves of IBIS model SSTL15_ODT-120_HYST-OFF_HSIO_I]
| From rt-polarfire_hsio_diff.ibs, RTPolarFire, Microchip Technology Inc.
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|   Model SSTL15_ODT-120_HYST-OFF_HSIO_I
[Model]   SSTL15_ODT-120_HYST-OFF_HSIO_I
Model_type   Input
Vinl =   0.65
Vinh =   0.85
|   typ   min   max
C_comp_pullup   1.335e-12   1.335e-12   1.380e-12
C_comp_pulldown  1.335e-12   1.335e-12   1.380e-12
[Temperature Range]  25C   125C   -55C
[Voltage Range]  1.5   1.425   1.575
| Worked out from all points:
|   POWER clamp passes 1 mA (typ) near -0.01 V on its own axis
[GND Clamp]
| Voltage   I(typ)   I(min)   I(max)
-984.4mV  -36.37mA   -30.39mA   -44.93mA
-738.3mV  -23.16mA   -19.44mA   -26.86mA
-541.4mV  -13.61mA   -12.33mA   -14.12mA
-393.7mV  -8.729mA   -8.495mA   -7.509mA
-295.3mV  -7.121mA   -6.919mA   -5.822mA
609.4mV   -1.187mA   -670uA     -1.138mA
1.406V    4.248mA    4.275mA    3.86mA
1.453V    4.515mA    0A         4.117mA
1.5V      4.781mA    0A         4.373mA
1.549V    0A         0A         4.642mA
1.746V    0A         0A         0A
3V        0A         0A         0A
[POWER Clamp]
| Voltage   I(typ)   I(min)   I(max)
-1.5V     74.73mA    64.82mA    98.06mA
-1.329V   61.5mA     53.47mA    81.6mA
-1.034V   41mA       35.04mA    54.79mA
-836.7mV  28.21mA    24.16mA    35.79mA
-689.1mV  19.28mA    17.13mA    22.36mA
-541.4mV  11.74mA    11.26mA    11.65mA
-443mV    8.344mA    8.333mA    7.852mA
-246.1mV  6.177mA    5.828mA    6.12mA
-49.22mV  5.061mA    4.646mA    2.177mA
0V        0A         1.812mA    748.3uA
46.88mV   0A         0A         0A
3V        0A         0A         0A
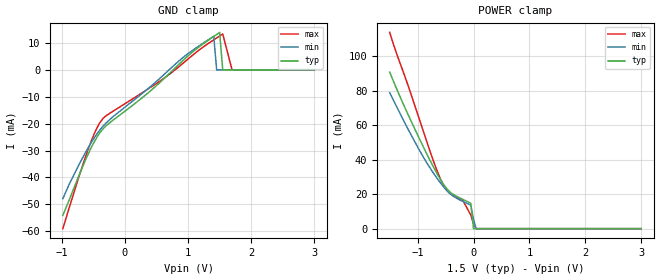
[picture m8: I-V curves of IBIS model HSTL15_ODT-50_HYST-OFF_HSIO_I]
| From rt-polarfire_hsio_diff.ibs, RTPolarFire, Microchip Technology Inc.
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|   Model HSTL15_ODT-50_HYST-OFF_HSIO_I
[Model]   HSTL15_ODT-50_HYST-OFF_HSIO_I
Model_type   Input
Vinl =   0.65
Vinh =   0.85
|   typ   min   max
C_comp_pullup   1.335e-12   1.335e-12   1.380e-12
C_comp_pulldown  1.335e-12   1.335e-12   1.380e-12
[Temperature Range]  25C   125C   -55C
[Voltage Range]  1.5   1.425   1.575
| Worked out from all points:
|   POWER clamp passes 1 mA (typ) near -0.00 V on its own axis
[GND Clamp]
| Voltage   I(typ)   I(min)   I(max)
-984.4mV  -54.1mA    -47.89mA   -59.03mA
-590.6mV  -31.66mA   -29.24mA   -29.99mA
-443mV    -24.97mA   -23.74mA   -21.53mA
-344.5mV  -21.82mA   -20.83mA   -17.98mA
421.9mV   -7.443mA   -5.844mA   -6.244mA
937.5mV   3.9mA      4.931mA    2.815mA
1.406V    12.43mA    12.53mA    11.16mA
1.453V    13.18mA    0A         11.88mA
1.5V      13.94mA    0A         12.59mA
1.549V    0A         0A         13.34mA
1.697V    0A         0A         0A
3V        0A         0A         0A
[POWER Clamp]
| Voltage   I(typ)   I(min)   I(max)
-1.5V     90.81mA    78.81mA    113.8mA
-1.28V    73.88mA    64.47mA    92.82mA
-984.4mV  53.2mA     46.39mA    64.91mA
-738.3mV  37.05mA    33.18mA    41.1mA
-590.6mV  28.4mA     26.42mA    28.69mA
-492.2mV  23.7mA     22.57mA    22.81mA
-443mV    21.89mA    20.94mA    20.96mA
-196.9mV  17.08mA    15.9mA     16.7mA
-49.22mV  14.73mA    13.59mA    7.911mA
0V        0A         5.304mA    2.72mA
46.88mV   0A         0A         0A
3V        0A         0A         0A
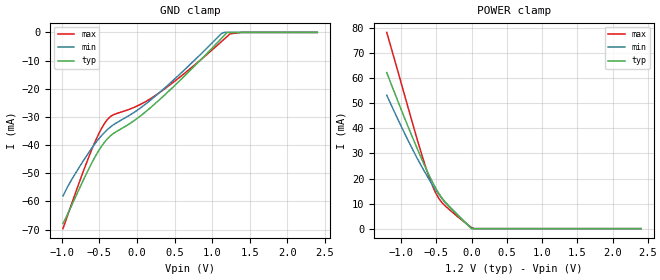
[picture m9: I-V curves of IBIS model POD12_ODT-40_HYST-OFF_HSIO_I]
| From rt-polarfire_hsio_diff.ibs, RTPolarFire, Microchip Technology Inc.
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|   Model POD12_ODT-40_HYST-OFF_HSIO_I
[Model]   POD12_ODT-40_HYST-OFF_HSIO_I
Model_type   Input
Vinl =   0.76
Vinh =   0.92
|   typ   min   max
C_comp_pullup   1.335e-12   1.335e-12   1.380e-12
C_comp_pulldown  1.335e-12   1.335e-12   1.380e-12
[Temperature Range]  25C   125C   -55C
[Voltage Range]  1.2   1.14   1.26
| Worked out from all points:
|   POWER clamp passes 1 mA (typ) near -0.04 V on its own axis
[GND Clamp]
| Voltage   I(typ)   I(min)   I(max)
-984.4mV  -67.85mA   -58.1mA    -69.69mA
-866.2mV  -61.27mA   -52.16mA   -60.64mA
-590.6mV  -45.82mA   -40.7mA    -40.91mA
-472.5mV  -40.48mA   -36.68mA   -34.15mA
-354.4mV  -36.76mA   -33.63mA   -29.9mA
0V        -30.62mA   -27.72mA   -26.18mA
262.5mV   -24.8mA    -22.22mA   -22.08mA
1.125V    -2.11mA    -403uA     -3.256mA
1.2V      474.1nA    0A         -1.454mA
1.239V    0A         0A         -500.6uA
1.397V    0A         0A         0A
2.4V      0A         0A         0A
[POWER Clamp]
| Voltage   I(typ)   I(min)   I(max)
-1.2V     62.25mA    53.22mA    78.28mA
-945mV    43.95mA    37.88mA    53.01mA
-748.1mV  30.58mA    27mA       33.64mA
-630mV    23.07mA    21.07mA    23.01mA
-551.3mV  18.5mA     17.4mA     17mA
-472.5mV  14.51mA    14.04mA    12.49mA
-393.7mV  11.36mA    11.1mA     9.649mA
-275.6mV  7.783mA    7.504mA    6.685mA
-39.38mV  1.112mA    1.067mA    1.267mA
0V        0A         244.2uA    435.4uA
37.5mV    0A         0A         0A
2.4V      0A         0A         0A
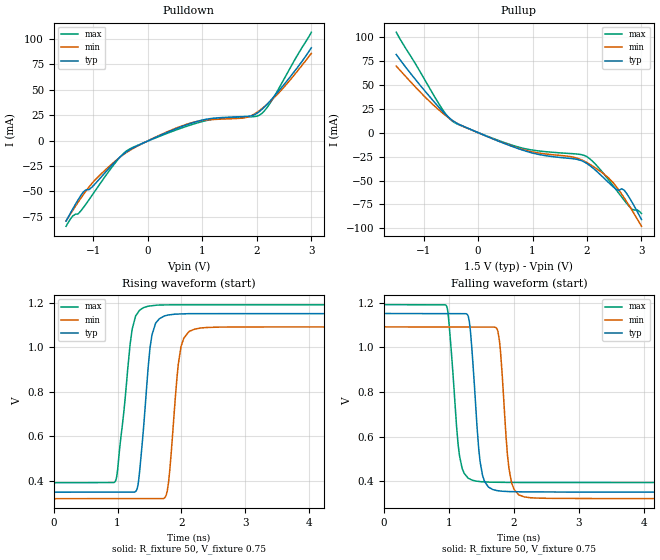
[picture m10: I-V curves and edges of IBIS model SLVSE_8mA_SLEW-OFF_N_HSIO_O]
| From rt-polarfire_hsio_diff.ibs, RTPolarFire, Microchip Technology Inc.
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|   Model SLVSE_8mA_SLEW-OFF_N_HSIO_O
[Model]   SLVSE_8mA_SLEW-OFF_N_HSIO_O
Model_type   Output
Polarity   Inverting
Enable   Active-High
Vmeas =   0.2
Cref =   5p
Rref =   100
|   typ   min   max
C_comp_pullup   1.335e-12   1.335e-12   1.380e-12
C_comp_pulldown  1.335e-12   1.335e-12   1.380e-12
[Temperature Range]  25C   125C   -55C
[Voltage Range]  1.5   1.425   1.575
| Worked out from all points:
|   slope of the pulldown table from 0 to 0.225 V, typ, clamps not added: 41.3 ohm
|   slope of the pullup table from 0 to 0.225 V, typ, clamps not added: 41.3 ohm
|   rising waveform, R_fixture 50, V_fixture 0.75: 20-80 % time 139ps typ, 133ps min, 170ps max; typ from 0.35 V to 1.15 V
|   falling waveform, R_fixture 50, V_fixture 0.75: 20-80 % time 118ps typ, 112ps min, 124ps max; typ from 1.15 V to 0.35 V
[Pulldown]
| Voltage   I(typ)   I(min)   I(max)
-1.5V     -79.31mA   -79.09mA   -84.42mA
-1.378V   -67.37mA   -68.77mA   -74.24mA
-1.181V   -50.43mA   -53.07mA   -65.92mA
-1.034V   -46.25mA   -42.66mA   -54.7mA
-590.6mV  -20.36mA   -19.87mA   -21.47mA
-295.3mV  -7.895mA   -8.466mA   -7.134mA
750mV     16.29mA    16.72mA    14.75mA
1.219V    22.12mA    20.83mA    21.22mA
1.746V    23.62mA    22.12mA    23.15mA
2.091V    30.58mA    31.32mA    26.64mA
2.288V    41.63mA    40.66mA    40.62mA
3V        91.4mA     85.89mA    106.7mA
[Pullup]
| Voltage   I(typ)   I(min)   I(max)
-1.5V     82.19mA    70mA       105.5mA
-689.1mV  25.02mA    22.61mA    27.84mA
-443mV    11.95mA    11.9mA     11.17mA
796.9mV   -17.71mA   -17.09mA   -15.72mA
1.697V    -26.83mA   -24.85mA   -21.7mA
1.992V    -31.94mA   -30.97mA   -24.77mA
2.386V    -51.58mA   -46.71mA   -48.55mA
2.583V    -60.43mA   -59.8mA    -63.25mA
2.681V    -60.01mA   -68.06mA   -70.58mA
2.829V    -72.94mA   -81.48mA   -80.19mA
2.927V    -83.06mA   -90.89mA   -80.93mA
3V        -90.94mA   -97.98mA   -84.59mA
[Ramp]
dV/dt_r   0.481251/0.13889n  0.46273/0.133218n  0.479464/0.170309n
dV/dt_f   0.481268/0.117679n  0.46275/0.112174n  0.47948/0.123577n
R_load = 50
[Rising Waveform]
R_fixture = 50
V_fixture = 0.75
V_fixture_min = 0.7125
V_fixture_max = 0.7875
| Time   V(typ)   V(min)   V(max)
0s        350mV      320.9mV    392.5mV
966ps     350.5mV    321.2mV    399.9mV
1.197ns   350.6mV    321.3mV    1.015V
1.308ns   367.1mV    321.3mV    1.151V
1.476ns   897.5mV    321.4mV    1.185V
1.596ns   1.108V     321.4mV    1.189V
1.763ns   1.143V     337.7mV    1.19V
1.994ns   1.15V      1.003V     1.191V
2.211ns   1.151V     1.082V     1.191V
10ns      1.152V     1.092V     1.192V
[Falling Waveform]
R_fixture = 50
V_fixture = 0.75
V_fixture_min = 0.7125
V_fixture_max = 0.7875
| Time   V(typ)   V(min)   V(max)
0s        1.152V     1.092V     1.192V
963ps     1.152V     1.092V     1.186V
1.164ns   1.152V     1.092V     513.4mV
1.359ns   975.5mV    1.092V     404.2mV
1.461ns   541.3mV    1.092V     398.5mV
1.549ns   399.5mV    1.091V     396.6mV
1.756ns   356.9mV    1.072V     394.8mV
1.926ns   353mV      456.9mV    394.2mV
2.164ns   351.7mV    329mV      393.9mV
10ns      350.3mV    321.1mV    393mV
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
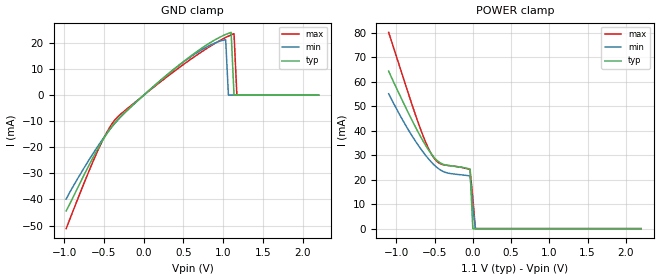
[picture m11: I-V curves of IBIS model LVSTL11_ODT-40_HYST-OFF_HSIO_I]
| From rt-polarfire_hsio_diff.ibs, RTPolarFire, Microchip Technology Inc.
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|   Model LVSTL11_ODT-40_HYST-OFF_HSIO_I
[Model]   LVSTL11_ODT-40_HYST-OFF_HSIO_I
Model_type   Input
Vinl =   0.083
Vinh =   0.283
|   typ   min   max
C_comp_pullup   1.335e-12   1.335e-12   1.380e-12
C_comp_pulldown  1.335e-12   1.335e-12   1.380e-12
[Temperature Range]  25C   125C   -55C
[Voltage Range]  1.1   1.045   1.155
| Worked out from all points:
|   GND clamp passes 1 mA (typ) near -0.03 V on its own axis
|   POWER clamp passes 1 mA (typ) near -0.00 V on its own axis
[GND Clamp]
| Voltage   I(typ)   I(min)   I(max)
-974.5mV  -44.41mA   -39.87mA   -51.19mA
-577.5mV  -20.6mA    -19.65mA   -21.34mA
-360.9mV  -10.54mA   -10.8mA    -9.495mA
446.9mV   11.56mA    11.45mA    10.54mA
756.2mV   18.52mA    17.85mA    17.15mA
996.9mV   22.78mA    21.01mA    21.55mA
1.031V    23.25mA    21.26mA    22.1mA
1.066V    23.67mA    0A         22.61mA
1.1V      24.04mA    0A         23.09mA
1.136V    0A         0A         23.55mA
1.172V    0A         0A         0A
2.2V      0A         0A         0A
[POWER Clamp]
| Voltage   I(typ)   I(min)   I(max)
-1.1V     64.4mA     55.15mA    80.24mA
-866.2mV  48.83mA    41.64mA    57.55mA
-721.9mV  39.9mA     34.48mA    44.05mA
-613.6mV  33.9mA     29.85mA    35.17mA
-541.4mV  30.51mA    27.2mA     30.5mA
-505.3mV  29.1mA     26.04mA    28.76mA
-433.1mV  27.03mA    24.18mA    26.67mA
-324.8mV  25.84mA    22.73mA    25.84mA
-36.09mV  24.38mA    21.55mA    24.14mA
0V        0A         8.589mA    12.55mA
34.38mV   0A         0A         0A
2.2V      0A         0A         0A
